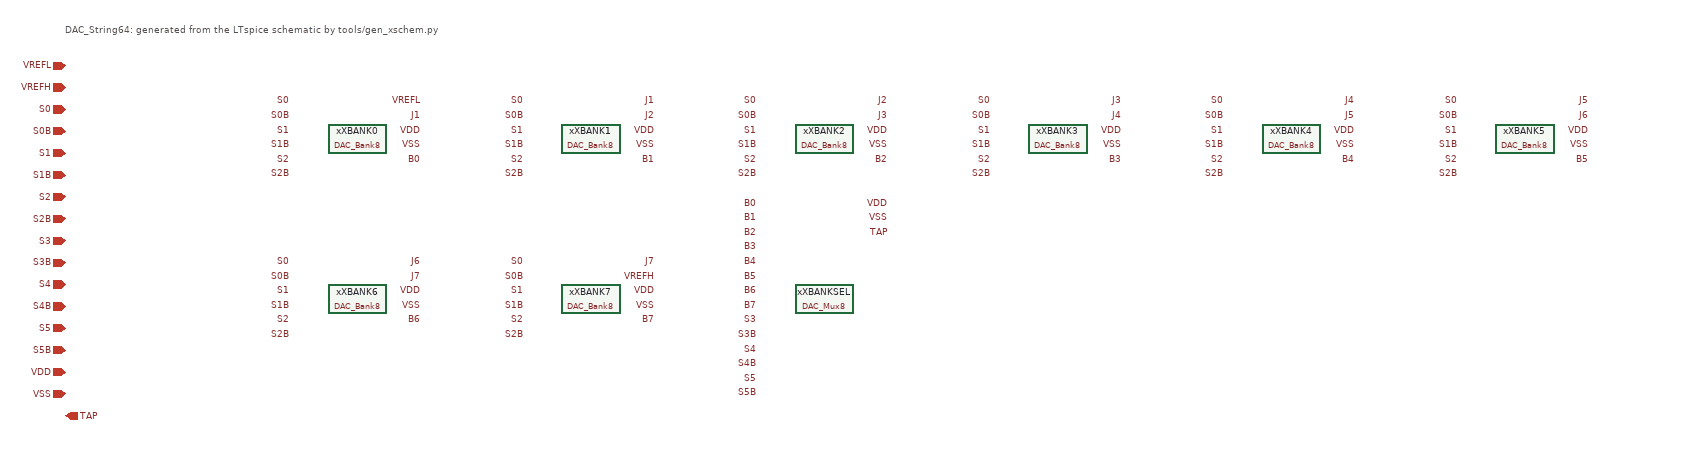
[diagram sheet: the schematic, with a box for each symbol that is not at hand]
v {xschem version=3.4.4 file_version=1.2
}
G {}
K {}
V {}
S {}
E {}
T {DAC_String64: generated from the LTspice schematic by tools/gen_xschem.py} -900 -560 0 0 0.4 0.4 {}
C {devices/iopin.sym} -900 -500 0 0 {name=p1 lab=VREFL}
C {devices/iopin.sym} -900 -470 0 0 {name=p2 lab=VREFH}
C {devices/ipin.sym} -900 -440 0 0 {name=p3 lab=S0}
C {devices/ipin.sym} -900 -410 0 0 {name=p4 lab=S0B}
C {devices/ipin.sym} -900 -380 0 0 {name=p5 lab=S1}
C {devices/ipin.sym} -900 -350 0 0 {name=p6 lab=S1B}
C {devices/ipin.sym} -900 -320 0 0 {name=p7 lab=S2}
C {devices/ipin.sym} -900 -290 0 0 {name=p8 lab=S2B}
C {devices/ipin.sym} -900 -260 0 0 {name=p9 lab=S3}
C {devices/ipin.sym} -900 -230 0 0 {name=p10 lab=S3B}
C {devices/ipin.sym} -900 -200 0 0 {name=p11 lab=S4}
C {devices/ipin.sym} -900 -170 0 0 {name=p12 lab=S4B}
C {devices/ipin.sym} -900 -140 0 0 {name=p13 lab=S5}
C {devices/ipin.sym} -900 -110 0 0 {name=p14 lab=S5B}
C {devices/iopin.sym} -900 -80 0 0 {name=p15 lab=VDD}
C {devices/iopin.sym} -900 -50 0 0 {name=p16 lab=VSS}
C {devices/opin.sym} -900 -20 0 0 {name=p17 lab=TAP}
C {DAC_Bank8.sym} -500 -400 0 0 {name=xXBANK0}
C {devices/lab_pin.sym} -410.0 -450.0 0 0 {name=l1 sig_type=std_logic lab=VREFL}
C {devices/lab_pin.sym} -410.0 -430.0 0 0 {name=l2 sig_type=std_logic lab=J1}
C {devices/lab_pin.sym} -590.0 -450.0 0 0 {name=l3 sig_type=std_logic lab=S0}
C {devices/lab_pin.sym} -590.0 -430.0 0 0 {name=l4 sig_type=std_logic lab=S0B}
C {devices/lab_pin.sym} -590.0 -410.0 0 0 {name=l5 sig_type=std_logic lab=S1}
C {devices/lab_pin.sym} -590.0 -390.0 0 0 {name=l6 sig_type=std_logic lab=S1B}
C {devices/lab_pin.sym} -590.0 -370.0 0 0 {name=l7 sig_type=std_logic lab=S2}
C {devices/lab_pin.sym} -590.0 -350.0 0 0 {name=l8 sig_type=std_logic lab=S2B}
C {devices/lab_pin.sym} -410.0 -410.0 0 0 {name=l9 sig_type=std_logic lab=VDD}
C {devices/lab_pin.sym} -410.0 -390.0 0 0 {name=l10 sig_type=std_logic lab=VSS}
C {devices/lab_pin.sym} -410.0 -370.0 0 0 {name=l11 sig_type=std_logic lab=B0}
C {DAC_Bank8.sym} -180 -400 0 0 {name=xXBANK1}
C {devices/lab_pin.sym} -90.0 -450.0 0 0 {name=l12 sig_type=std_logic lab=J1}
C {devices/lab_pin.sym} -90.0 -430.0 0 0 {name=l13 sig_type=std_logic lab=J2}
C {devices/lab_pin.sym} -270.0 -450.0 0 0 {name=l14 sig_type=std_logic lab=S0}
C {devices/lab_pin.sym} -270.0 -430.0 0 0 {name=l15 sig_type=std_logic lab=S0B}
C {devices/lab_pin.sym} -270.0 -410.0 0 0 {name=l16 sig_type=std_logic lab=S1}
C {devices/lab_pin.sym} -270.0 -390.0 0 0 {name=l17 sig_type=std_logic lab=S1B}
C {devices/lab_pin.sym} -270.0 -370.0 0 0 {name=l18 sig_type=std_logic lab=S2}
C {devices/lab_pin.sym} -270.0 -350.0 0 0 {name=l19 sig_type=std_logic lab=S2B}
C {devices/lab_pin.sym} -90.0 -410.0 0 0 {name=l20 sig_type=std_logic lab=VDD}
C {devices/lab_pin.sym} -90.0 -390.0 0 0 {name=l21 sig_type=std_logic lab=VSS}
C {devices/lab_pin.sym} -90.0 -370.0 0 0 {name=l22 sig_type=std_logic lab=B1}
C {DAC_Bank8.sym} 140 -400 0 0 {name=xXBANK2}
C {devices/lab_pin.sym} 230.0 -450.0 0 0 {name=l23 sig_type=std_logic lab=J2}
C {devices/lab_pin.sym} 230.0 -430.0 0 0 {name=l24 sig_type=std_logic lab=J3}
C {devices/lab_pin.sym} 50.0 -450.0 0 0 {name=l25 sig_type=std_logic lab=S0}
C {devices/lab_pin.sym} 50.0 -430.0 0 0 {name=l26 sig_type=std_logic lab=S0B}
C {devices/lab_pin.sym} 50.0 -410.0 0 0 {name=l27 sig_type=std_logic lab=S1}
C {devices/lab_pin.sym} 50.0 -390.0 0 0 {name=l28 sig_type=std_logic lab=S1B}
C {devices/lab_pin.sym} 50.0 -370.0 0 0 {name=l29 sig_type=std_logic lab=S2}
C {devices/lab_pin.sym} 50.0 -350.0 0 0 {name=l30 sig_type=std_logic lab=S2B}
C {devices/lab_pin.sym} 230.0 -410.0 0 0 {name=l31 sig_type=std_logic lab=VDD}
C {devices/lab_pin.sym} 230.0 -390.0 0 0 {name=l32 sig_type=std_logic lab=VSS}
C {devices/lab_pin.sym} 230.0 -370.0 0 0 {name=l33 sig_type=std_logic lab=B2}
C {DAC_Bank8.sym} 460 -400 0 0 {name=xXBANK3}
C {devices/lab_pin.sym} 550.0 -450.0 0 0 {name=l34 sig_type=std_logic lab=J3}
C {devices/lab_pin.sym} 550.0 -430.0 0 0 {name=l35 sig_type=std_logic lab=J4}
C {devices/lab_pin.sym} 370.0 -450.0 0 0 {name=l36 sig_type=std_logic lab=S0}
C {devices/lab_pin.sym} 370.0 -430.0 0 0 {name=l37 sig_type=std_logic lab=S0B}
C {devices/lab_pin.sym} 370.0 -410.0 0 0 {name=l38 sig_type=std_logic lab=S1}
C {devices/lab_pin.sym} 370.0 -390.0 0 0 {name=l39 sig_type=std_logic lab=S1B}
C {devices/lab_pin.sym} 370.0 -370.0 0 0 {name=l40 sig_type=std_logic lab=S2}
C {devices/lab_pin.sym} 370.0 -350.0 0 0 {name=l41 sig_type=std_logic lab=S2B}
C {devices/lab_pin.sym} 550.0 -410.0 0 0 {name=l42 sig_type=std_logic lab=VDD}
C {devices/lab_pin.sym} 550.0 -390.0 0 0 {name=l43 sig_type=std_logic lab=VSS}
C {devices/lab_pin.sym} 550.0 -370.0 0 0 {name=l44 sig_type=std_logic lab=B3}
C {DAC_Bank8.sym} 780 -400 0 0 {name=xXBANK4}
C {devices/lab_pin.sym} 870.0 -450.0 0 0 {name=l45 sig_type=std_logic lab=J4}
C {devices/lab_pin.sym} 870.0 -430.0 0 0 {name=l46 sig_type=std_logic lab=J5}
C {devices/lab_pin.sym} 690.0 -450.0 0 0 {name=l47 sig_type=std_logic lab=S0}
C {devices/lab_pin.sym} 690.0 -430.0 0 0 {name=l48 sig_type=std_logic lab=S0B}
C {devices/lab_pin.sym} 690.0 -410.0 0 0 {name=l49 sig_type=std_logic lab=S1}
C {devices/lab_pin.sym} 690.0 -390.0 0 0 {name=l50 sig_type=std_logic lab=S1B}
C {devices/lab_pin.sym} 690.0 -370.0 0 0 {name=l51 sig_type=std_logic lab=S2}
C {devices/lab_pin.sym} 690.0 -350.0 0 0 {name=l52 sig_type=std_logic lab=S2B}
C {devices/lab_pin.sym} 870.0 -410.0 0 0 {name=l53 sig_type=std_logic lab=VDD}
C {devices/lab_pin.sym} 870.0 -390.0 0 0 {name=l54 sig_type=std_logic lab=VSS}
C {devices/lab_pin.sym} 870.0 -370.0 0 0 {name=l55 sig_type=std_logic lab=B4}
C {DAC_Bank8.sym} 1100 -400 0 0 {name=xXBANK5}
C {devices/lab_pin.sym} 1190.0 -450.0 0 0 {name=l56 sig_type=std_logic lab=J5}
C {devices/lab_pin.sym} 1190.0 -430.0 0 0 {name=l57 sig_type=std_logic lab=J6}
C {devices/lab_pin.sym} 1010.0 -450.0 0 0 {name=l58 sig_type=std_logic lab=S0}
C {devices/lab_pin.sym} 1010.0 -430.0 0 0 {name=l59 sig_type=std_logic lab=S0B}
C {devices/lab_pin.sym} 1010.0 -410.0 0 0 {name=l60 sig_type=std_logic lab=S1}
C {devices/lab_pin.sym} 1010.0 -390.0 0 0 {name=l61 sig_type=std_logic lab=S1B}
C {devices/lab_pin.sym} 1010.0 -370.0 0 0 {name=l62 sig_type=std_logic lab=S2}
C {devices/lab_pin.sym} 1010.0 -350.0 0 0 {name=l63 sig_type=std_logic lab=S2B}
C {devices/lab_pin.sym} 1190.0 -410.0 0 0 {name=l64 sig_type=std_logic lab=VDD}
C {devices/lab_pin.sym} 1190.0 -390.0 0 0 {name=l65 sig_type=std_logic lab=VSS}
C {devices/lab_pin.sym} 1190.0 -370.0 0 0 {name=l66 sig_type=std_logic lab=B5}
C {DAC_Bank8.sym} -500 -180 0 0 {name=xXBANK6}
C {devices/lab_pin.sym} -410.0 -230.0 0 0 {name=l67 sig_type=std_logic lab=J6}
C {devices/lab_pin.sym} -410.0 -210.0 0 0 {name=l68 sig_type=std_logic lab=J7}
C {devices/lab_pin.sym} -590.0 -230.0 0 0 {name=l69 sig_type=std_logic lab=S0}
C {devices/lab_pin.sym} -590.0 -210.0 0 0 {name=l70 sig_type=std_logic lab=S0B}
C {devices/lab_pin.sym} -590.0 -190.0 0 0 {name=l71 sig_type=std_logic lab=S1}
C {devices/lab_pin.sym} -590.0 -170.0 0 0 {name=l72 sig_type=std_logic lab=S1B}
C {devices/lab_pin.sym} -590.0 -150.0 0 0 {name=l73 sig_type=std_logic lab=S2}
C {devices/lab_pin.sym} -590.0 -130.0 0 0 {name=l74 sig_type=std_logic lab=S2B}
C {devices/lab_pin.sym} -410.0 -190.0 0 0 {name=l75 sig_type=std_logic lab=VDD}
C {devices/lab_pin.sym} -410.0 -170.0 0 0 {name=l76 sig_type=std_logic lab=VSS}
C {devices/lab_pin.sym} -410.0 -150.0 0 0 {name=l77 sig_type=std_logic lab=B6}
C {DAC_Bank8.sym} -180 -180 0 0 {name=xXBANK7}
C {devices/lab_pin.sym} -90.0 -230.0 0 0 {name=l78 sig_type=std_logic lab=J7}
C {devices/lab_pin.sym} -90.0 -210.0 0 0 {name=l79 sig_type=std_logic lab=VREFH}
C {devices/lab_pin.sym} -270.0 -230.0 0 0 {name=l80 sig_type=std_logic lab=S0}
C {devices/lab_pin.sym} -270.0 -210.0 0 0 {name=l81 sig_type=std_logic lab=S0B}
C {devices/lab_pin.sym} -270.0 -190.0 0 0 {name=l82 sig_type=std_logic lab=S1}
C {devices/lab_pin.sym} -270.0 -170.0 0 0 {name=l83 sig_type=std_logic lab=S1B}
C {devices/lab_pin.sym} -270.0 -150.0 0 0 {name=l84 sig_type=std_logic lab=S2}
C {devices/lab_pin.sym} -270.0 -130.0 0 0 {name=l85 sig_type=std_logic lab=S2B}
C {devices/lab_pin.sym} -90.0 -190.0 0 0 {name=l86 sig_type=std_logic lab=VDD}
C {devices/lab_pin.sym} -90.0 -170.0 0 0 {name=l87 sig_type=std_logic lab=VSS}
C {devices/lab_pin.sym} -90.0 -150.0 0 0 {name=l88 sig_type=std_logic lab=B7}
C {DAC_Mux8.sym} 140 -180 0 0 {name=xXBANKSEL}
C {devices/lab_pin.sym} 50.0 -310.0 0 0 {name=l89 sig_type=std_logic lab=B0}
C {devices/lab_pin.sym} 50.0 -290.0 0 0 {name=l90 sig_type=std_logic lab=B1}
C {devices/lab_pin.sym} 50.0 -270.0 0 0 {name=l91 sig_type=std_logic lab=B2}
C {devices/lab_pin.sym} 50.0 -250.0 0 0 {name=l92 sig_type=std_logic lab=B3}
C {devices/lab_pin.sym} 50.0 -230.0 0 0 {name=l93 sig_type=std_logic lab=B4}
C {devices/lab_pin.sym} 50.0 -210.0 0 0 {name=l94 sig_type=std_logic lab=B5}
C {devices/lab_pin.sym} 50.0 -190.0 0 0 {name=l95 sig_type=std_logic lab=B6}
C {devices/lab_pin.sym} 50.0 -170.0 0 0 {name=l96 sig_type=std_logic lab=B7}
C {devices/lab_pin.sym} 50.0 -150.0 0 0 {name=l97 sig_type=std_logic lab=S3}
C {devices/lab_pin.sym} 50.0 -130.0 0 0 {name=l98 sig_type=std_logic lab=S3B}
C {devices/lab_pin.sym} 50.0 -110.0 0 0 {name=l99 sig_type=std_logic lab=S4}
C {devices/lab_pin.sym} 50.0 -90.0 0 0 {name=l100 sig_type=std_logic lab=S4B}
C {devices/lab_pin.sym} 50.0 -70.0 0 0 {name=l101 sig_type=std_logic lab=S5}
C {devices/lab_pin.sym} 50.0 -50.0 0 0 {name=l102 sig_type=std_logic lab=S5B}
C {devices/lab_pin.sym} 230.0 -310.0 0 0 {name=l103 sig_type=std_logic lab=VDD}
C {devices/lab_pin.sym} 230.0 -290.0 0 0 {name=l104 sig_type=std_logic lab=VSS}
C {devices/lab_pin.sym} 230.0 -270.0 0 0 {name=l105 sig_type=std_logic lab=TAP}
